VERSION 5.7 ;
BUSBITCHARS "[]" ;
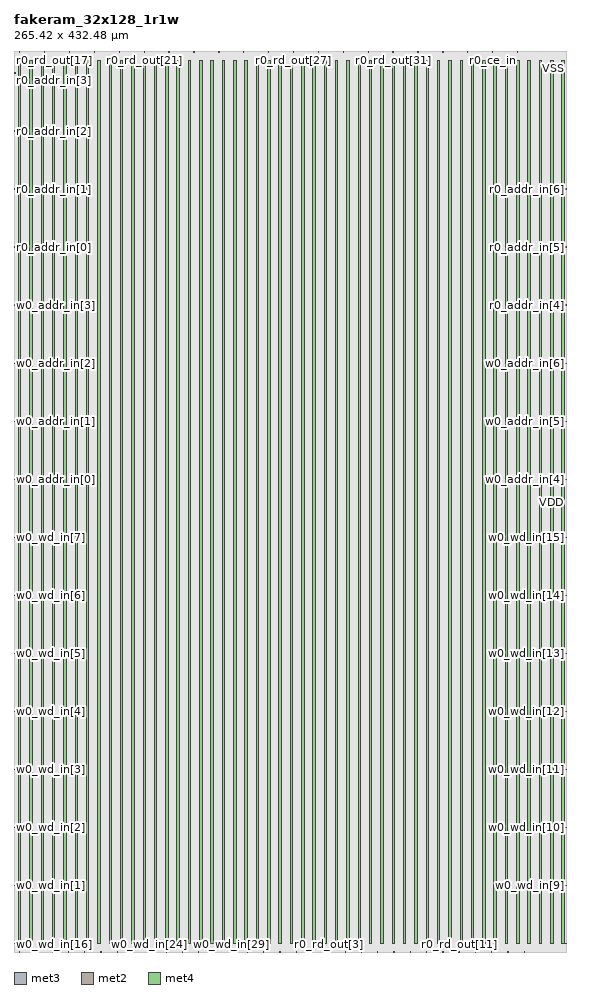
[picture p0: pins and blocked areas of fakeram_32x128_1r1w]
MACRO fakeram_32x128_1r1w
  FOREIGN fakeram_32x128_1r1w 0 0 ;
  SYMMETRY X Y R90 ;
  SIZE 265.420 BY 432.480 ;
  CLASS BLOCK ;
  PIN w0_wd_in[0]
    DIRECTION INPUT ;
    USE SIGNAL ;
    SHAPE ABUTMENT ;
    PORT
      LAYER met3 ;
      RECT 0.000 3.930 0.900 4.230 ;
    END
  END w0_wd_in[0]
  PIN w0_wd_in[1]
    DIRECTION INPUT ;
    USE SIGNAL ;
    SHAPE ABUTMENT ;
    PORT
      LAYER met3 ;
      RECT 0.000 31.810 0.900 32.110 ;
    END
  END w0_wd_in[1]
  PIN w0_wd_in[2]
    DIRECTION INPUT ;
    USE SIGNAL ;
    SHAPE ABUTMENT ;
    PORT
      LAYER met3 ;
      RECT 0.000 59.690 0.900 59.990 ;
    END
  END w0_wd_in[2]
  PIN w0_wd_in[3]
    DIRECTION INPUT ;
    USE SIGNAL ;
    SHAPE ABUTMENT ;
    PORT
      LAYER met3 ;
      RECT 0.000 87.570 0.900 87.870 ;
    END
  END w0_wd_in[3]
  PIN w0_wd_in[4]
    DIRECTION INPUT ;
    USE SIGNAL ;
    SHAPE ABUTMENT ;
    PORT
      LAYER met3 ;
      RECT 0.000 115.450 0.900 115.750 ;
    END
  END w0_wd_in[4]
  PIN w0_wd_in[5]
    DIRECTION INPUT ;
    USE SIGNAL ;
    SHAPE ABUTMENT ;
    PORT
      LAYER met3 ;
      RECT 0.000 143.330 0.900 143.630 ;
    END
  END w0_wd_in[5]
  PIN w0_wd_in[6]
    DIRECTION INPUT ;
    USE SIGNAL ;
    SHAPE ABUTMENT ;
    PORT
      LAYER met3 ;
      RECT 0.000 171.210 0.900 171.510 ;
    END
  END w0_wd_in[6]
  PIN w0_wd_in[7]
    DIRECTION INPUT ;
    USE SIGNAL ;
    SHAPE ABUTMENT ;
    PORT
      LAYER met3 ;
      RECT 0.000 199.090 0.900 199.390 ;
    END
  END w0_wd_in[7]
  PIN w0_wd_in[8]
    DIRECTION INPUT ;
    USE SIGNAL ;
    SHAPE ABUTMENT ;
    PORT
      LAYER met3 ;
      RECT 264.520 3.930 265.420 4.230 ;
    END
  END w0_wd_in[8]
  PIN w0_wd_in[9]
    DIRECTION INPUT ;
    USE SIGNAL ;
    SHAPE ABUTMENT ;
    PORT
      LAYER met3 ;
      RECT 264.520 31.810 265.420 32.110 ;
    END
  END w0_wd_in[9]
  PIN w0_wd_in[10]
    DIRECTION INPUT ;
    USE SIGNAL ;
    SHAPE ABUTMENT ;
    PORT
      LAYER met3 ;
      RECT 264.520 59.690 265.420 59.990 ;
    END
  END w0_wd_in[10]
  PIN w0_wd_in[11]
    DIRECTION INPUT ;
    USE SIGNAL ;
    SHAPE ABUTMENT ;
    PORT
      LAYER met3 ;
      RECT 264.520 87.570 265.420 87.870 ;
    END
  END w0_wd_in[11]
  PIN w0_wd_in[12]
    DIRECTION INPUT ;
    USE SIGNAL ;
    SHAPE ABUTMENT ;
    PORT
      LAYER met3 ;
      RECT 264.520 115.450 265.420 115.750 ;
    END
  END w0_wd_in[12]
  PIN w0_wd_in[13]
    DIRECTION INPUT ;
    USE SIGNAL ;
    SHAPE ABUTMENT ;
    PORT
      LAYER met3 ;
      RECT 264.520 143.330 265.420 143.630 ;
    END
  END w0_wd_in[13]
  PIN w0_wd_in[14]
    DIRECTION INPUT ;
    USE SIGNAL ;
    SHAPE ABUTMENT ;
    PORT
      LAYER met3 ;
      RECT 264.520 171.210 265.420 171.510 ;
    END
  END w0_wd_in[14]
  PIN w0_wd_in[15]
    DIRECTION INPUT ;
    USE SIGNAL ;
    SHAPE ABUTMENT ;
    PORT
      LAYER met3 ;
      RECT 264.520 199.090 265.420 199.390 ;
    END
  END w0_wd_in[15]
  PIN w0_wd_in[16]
    DIRECTION INPUT ;
    USE SIGNAL ;
    SHAPE ABUTMENT ;
    PORT
      LAYER met2 ;
      RECT 2.690 0.000 2.830 0.420 ;
    END
  END w0_wd_in[16]
  PIN w0_wd_in[17]
    DIRECTION INPUT ;
    USE SIGNAL ;
    SHAPE ABUTMENT ;
    PORT
      LAYER met2 ;
      RECT 10.510 0.000 10.650 0.420 ;
    END
  END w0_wd_in[17]
  PIN w0_wd_in[18]
    DIRECTION INPUT ;
    USE SIGNAL ;
    SHAPE ABUTMENT ;
    PORT
      LAYER met2 ;
      RECT 18.330 0.000 18.470 0.420 ;
    END
  END w0_wd_in[18]
  PIN w0_wd_in[19]
    DIRECTION INPUT ;
    USE SIGNAL ;
    SHAPE ABUTMENT ;
    PORT
      LAYER met2 ;
      RECT 26.150 0.000 26.290 0.420 ;
    END
  END w0_wd_in[19]
  PIN w0_wd_in[20]
    DIRECTION INPUT ;
    USE SIGNAL ;
    SHAPE ABUTMENT ;
    PORT
      LAYER met2 ;
      RECT 33.970 0.000 34.110 0.420 ;
    END
  END w0_wd_in[20]
  PIN w0_wd_in[21]
    DIRECTION INPUT ;
    USE SIGNAL ;
    SHAPE ABUTMENT ;
    PORT
      LAYER met2 ;
      RECT 41.790 0.000 41.930 0.420 ;
    END
  END w0_wd_in[21]
  PIN w0_wd_in[22]
    DIRECTION INPUT ;
    USE SIGNAL ;
    SHAPE ABUTMENT ;
    PORT
      LAYER met2 ;
      RECT 49.610 0.000 49.750 0.420 ;
    END
  END w0_wd_in[22]
  PIN w0_wd_in[23]
    DIRECTION INPUT ;
    USE SIGNAL ;
    SHAPE ABUTMENT ;
    PORT
      LAYER met2 ;
      RECT 57.430 0.000 57.570 0.420 ;
    END
  END w0_wd_in[23]
  PIN w0_wd_in[24]
    DIRECTION INPUT ;
    USE SIGNAL ;
    SHAPE ABUTMENT ;
    PORT
      LAYER met2 ;
      RECT 65.250 0.000 65.390 0.420 ;
    END
  END w0_wd_in[24]
  PIN w0_wd_in[25]
    DIRECTION INPUT ;
    USE SIGNAL ;
    SHAPE ABUTMENT ;
    PORT
      LAYER met2 ;
      RECT 73.070 0.000 73.210 0.420 ;
    END
  END w0_wd_in[25]
  PIN w0_wd_in[26]
    DIRECTION INPUT ;
    USE SIGNAL ;
    SHAPE ABUTMENT ;
    PORT
      LAYER met2 ;
      RECT 80.890 0.000 81.030 0.420 ;
    END
  END w0_wd_in[26]
  PIN w0_wd_in[27]
    DIRECTION INPUT ;
    USE SIGNAL ;
    SHAPE ABUTMENT ;
    PORT
      LAYER met2 ;
      RECT 88.710 0.000 88.850 0.420 ;
    END
  END w0_wd_in[27]
  PIN w0_wd_in[28]
    DIRECTION INPUT ;
    USE SIGNAL ;
    SHAPE ABUTMENT ;
    PORT
      LAYER met2 ;
      RECT 96.530 0.000 96.670 0.420 ;
    END
  END w0_wd_in[28]
  PIN w0_wd_in[29]
    DIRECTION INPUT ;
    USE SIGNAL ;
    SHAPE ABUTMENT ;
    PORT
      LAYER met2 ;
      RECT 104.350 0.000 104.490 0.420 ;
    END
  END w0_wd_in[29]
  PIN w0_wd_in[30]
    DIRECTION INPUT ;
    USE SIGNAL ;
    SHAPE ABUTMENT ;
    PORT
      LAYER met2 ;
      RECT 112.170 0.000 112.310 0.420 ;
    END
  END w0_wd_in[30]
  PIN w0_wd_in[31]
    DIRECTION INPUT ;
    USE SIGNAL ;
    SHAPE ABUTMENT ;
    PORT
      LAYER met2 ;
      RECT 119.990 0.000 120.130 0.420 ;
    END
  END w0_wd_in[31]
  PIN r0_rd_out[0]
    DIRECTION OUTPUT ;
    USE SIGNAL ;
    SHAPE ABUTMENT ;
    PORT
      LAYER met2 ;
      RECT 127.810 0.000 127.950 0.420 ;
    END
  END r0_rd_out[0]
  PIN r0_rd_out[1]
    DIRECTION OUTPUT ;
    USE SIGNAL ;
    SHAPE ABUTMENT ;
    PORT
      LAYER met2 ;
      RECT 135.630 0.000 135.770 0.420 ;
    END
  END r0_rd_out[1]
  PIN r0_rd_out[2]
    DIRECTION OUTPUT ;
    USE SIGNAL ;
    SHAPE ABUTMENT ;
    PORT
      LAYER met2 ;
      RECT 143.450 0.000 143.590 0.420 ;
    END
  END r0_rd_out[2]
  PIN r0_rd_out[3]
    DIRECTION OUTPUT ;
    USE SIGNAL ;
    SHAPE ABUTMENT ;
    PORT
      LAYER met2 ;
      RECT 151.270 0.000 151.410 0.420 ;
    END
  END r0_rd_out[3]
  PIN r0_rd_out[4]
    DIRECTION OUTPUT ;
    USE SIGNAL ;
    SHAPE ABUTMENT ;
    PORT
      LAYER met2 ;
      RECT 159.090 0.000 159.230 0.420 ;
    END
  END r0_rd_out[4]
  PIN r0_rd_out[5]
    DIRECTION OUTPUT ;
    USE SIGNAL ;
    SHAPE ABUTMENT ;
    PORT
      LAYER met2 ;
      RECT 166.910 0.000 167.050 0.420 ;
    END
  END r0_rd_out[5]
  PIN r0_rd_out[6]
    DIRECTION OUTPUT ;
    USE SIGNAL ;
    SHAPE ABUTMENT ;
    PORT
      LAYER met2 ;
      RECT 174.730 0.000 174.870 0.420 ;
    END
  END r0_rd_out[6]
  PIN r0_rd_out[7]
    DIRECTION OUTPUT ;
    USE SIGNAL ;
    SHAPE ABUTMENT ;
    PORT
      LAYER met2 ;
      RECT 182.550 0.000 182.690 0.420 ;
    END
  END r0_rd_out[7]
  PIN r0_rd_out[8]
    DIRECTION OUTPUT ;
    USE SIGNAL ;
    SHAPE ABUTMENT ;
    PORT
      LAYER met2 ;
      RECT 190.370 0.000 190.510 0.420 ;
    END
  END r0_rd_out[8]
  PIN r0_rd_out[9]
    DIRECTION OUTPUT ;
    USE SIGNAL ;
    SHAPE ABUTMENT ;
    PORT
      LAYER met2 ;
      RECT 198.190 0.000 198.330 0.420 ;
    END
  END r0_rd_out[9]
  PIN r0_rd_out[10]
    DIRECTION OUTPUT ;
    USE SIGNAL ;
    SHAPE ABUTMENT ;
    PORT
      LAYER met2 ;
      RECT 206.010 0.000 206.150 0.420 ;
    END
  END r0_rd_out[10]
  PIN r0_rd_out[11]
    DIRECTION OUTPUT ;
    USE SIGNAL ;
    SHAPE ABUTMENT ;
    PORT
      LAYER met2 ;
      RECT 213.830 0.000 213.970 0.420 ;
    END
  END r0_rd_out[11]
  PIN r0_rd_out[12]
    DIRECTION OUTPUT ;
    USE SIGNAL ;
    SHAPE ABUTMENT ;
    PORT
      LAYER met2 ;
      RECT 221.650 0.000 221.790 0.420 ;
    END
  END r0_rd_out[12]
  PIN r0_rd_out[13]
    DIRECTION OUTPUT ;
    USE SIGNAL ;
    SHAPE ABUTMENT ;
    PORT
      LAYER met2 ;
      RECT 229.470 0.000 229.610 0.420 ;
    END
  END r0_rd_out[13]
  PIN r0_rd_out[14]
    DIRECTION OUTPUT ;
    USE SIGNAL ;
    SHAPE ABUTMENT ;
    PORT
      LAYER met2 ;
      RECT 237.290 0.000 237.430 0.420 ;
    END
  END r0_rd_out[14]
  PIN r0_rd_out[15]
    DIRECTION OUTPUT ;
    USE SIGNAL ;
    SHAPE ABUTMENT ;
    PORT
      LAYER met2 ;
      RECT 245.110 0.000 245.250 0.420 ;
    END
  END r0_rd_out[15]
  PIN r0_rd_out[16]
    DIRECTION OUTPUT ;
    USE SIGNAL ;
    SHAPE ABUTMENT ;
    PORT
      LAYER met2 ;
      RECT 2.690 432.060 2.830 432.480 ;
    END
  END r0_rd_out[16]
  PIN r0_rd_out[17]
    DIRECTION OUTPUT ;
    USE SIGNAL ;
    SHAPE ABUTMENT ;
    PORT
      LAYER met2 ;
      RECT 14.650 432.060 14.790 432.480 ;
    END
  END r0_rd_out[17]
  PIN r0_rd_out[18]
    DIRECTION OUTPUT ;
    USE SIGNAL ;
    SHAPE ABUTMENT ;
    PORT
      LAYER met2 ;
      RECT 26.610 432.060 26.750 432.480 ;
    END
  END r0_rd_out[18]
  PIN r0_rd_out[19]
    DIRECTION OUTPUT ;
    USE SIGNAL ;
    SHAPE ABUTMENT ;
    PORT
      LAYER met2 ;
      RECT 38.570 432.060 38.710 432.480 ;
    END
  END r0_rd_out[19]
  PIN r0_rd_out[20]
    DIRECTION OUTPUT ;
    USE SIGNAL ;
    SHAPE ABUTMENT ;
    PORT
      LAYER met2 ;
      RECT 50.530 432.060 50.670 432.480 ;
    END
  END r0_rd_out[20]
  PIN r0_rd_out[21]
    DIRECTION OUTPUT ;
    USE SIGNAL ;
    SHAPE ABUTMENT ;
    PORT
      LAYER met2 ;
      RECT 62.490 432.060 62.630 432.480 ;
    END
  END r0_rd_out[21]
  PIN r0_rd_out[22]
    DIRECTION OUTPUT ;
    USE SIGNAL ;
    SHAPE ABUTMENT ;
    PORT
      LAYER met2 ;
      RECT 74.450 432.060 74.590 432.480 ;
    END
  END r0_rd_out[22]
  PIN r0_rd_out[23]
    DIRECTION OUTPUT ;
    USE SIGNAL ;
    SHAPE ABUTMENT ;
    PORT
      LAYER met2 ;
      RECT 86.410 432.060 86.550 432.480 ;
    END
  END r0_rd_out[23]
  PIN r0_rd_out[24]
    DIRECTION OUTPUT ;
    USE SIGNAL ;
    SHAPE ABUTMENT ;
    PORT
      LAYER met2 ;
      RECT 98.370 432.060 98.510 432.480 ;
    END
  END r0_rd_out[24]
  PIN r0_rd_out[25]
    DIRECTION OUTPUT ;
    USE SIGNAL ;
    SHAPE ABUTMENT ;
    PORT
      LAYER met2 ;
      RECT 110.330 432.060 110.470 432.480 ;
    END
  END r0_rd_out[25]
  PIN r0_rd_out[26]
    DIRECTION OUTPUT ;
    USE SIGNAL ;
    SHAPE ABUTMENT ;
    PORT
      LAYER met2 ;
      RECT 122.290 432.060 122.430 432.480 ;
    END
  END r0_rd_out[26]
  PIN r0_rd_out[27]
    DIRECTION OUTPUT ;
    USE SIGNAL ;
    SHAPE ABUTMENT ;
    PORT
      LAYER met2 ;
      RECT 134.250 432.060 134.390 432.480 ;
    END
  END r0_rd_out[27]
  PIN r0_rd_out[28]
    DIRECTION OUTPUT ;
    USE SIGNAL ;
    SHAPE ABUTMENT ;
    PORT
      LAYER met2 ;
      RECT 146.210 432.060 146.350 432.480 ;
    END
  END r0_rd_out[28]
  PIN r0_rd_out[29]
    DIRECTION OUTPUT ;
    USE SIGNAL ;
    SHAPE ABUTMENT ;
    PORT
      LAYER met2 ;
      RECT 158.170 432.060 158.310 432.480 ;
    END
  END r0_rd_out[29]
  PIN r0_rd_out[30]
    DIRECTION OUTPUT ;
    USE SIGNAL ;
    SHAPE ABUTMENT ;
    PORT
      LAYER met2 ;
      RECT 170.130 432.060 170.270 432.480 ;
    END
  END r0_rd_out[30]
  PIN r0_rd_out[31]
    DIRECTION OUTPUT ;
    USE SIGNAL ;
    SHAPE ABUTMENT ;
    PORT
      LAYER met2 ;
      RECT 182.090 432.060 182.230 432.480 ;
    END
  END r0_rd_out[31]
  PIN w0_addr_in[0]
    DIRECTION INPUT ;
    USE SIGNAL ;
    SHAPE ABUTMENT ;
    PORT
      LAYER met3 ;
      RECT 0.000 226.970 0.900 227.270 ;
    END
  END w0_addr_in[0]
  PIN w0_addr_in[1]
    DIRECTION INPUT ;
    USE SIGNAL ;
    SHAPE ABUTMENT ;
    PORT
      LAYER met3 ;
      RECT 0.000 254.850 0.900 255.150 ;
    END
  END w0_addr_in[1]
  PIN w0_addr_in[2]
    DIRECTION INPUT ;
    USE SIGNAL ;
    SHAPE ABUTMENT ;
    PORT
      LAYER met3 ;
      RECT 0.000 282.730 0.900 283.030 ;
    END
  END w0_addr_in[2]
  PIN w0_addr_in[3]
    DIRECTION INPUT ;
    USE SIGNAL ;
    SHAPE ABUTMENT ;
    PORT
      LAYER met3 ;
      RECT 0.000 310.610 0.900 310.910 ;
    END
  END w0_addr_in[3]
  PIN w0_addr_in[4]
    DIRECTION INPUT ;
    USE SIGNAL ;
    SHAPE ABUTMENT ;
    PORT
      LAYER met3 ;
      RECT 264.520 226.970 265.420 227.270 ;
    END
  END w0_addr_in[4]
  PIN w0_addr_in[5]
    DIRECTION INPUT ;
    USE SIGNAL ;
    SHAPE ABUTMENT ;
    PORT
      LAYER met3 ;
      RECT 264.520 254.850 265.420 255.150 ;
    END
  END w0_addr_in[5]
  PIN w0_addr_in[6]
    DIRECTION INPUT ;
    USE SIGNAL ;
    SHAPE ABUTMENT ;
    PORT
      LAYER met3 ;
      RECT 264.520 282.730 265.420 283.030 ;
    END
  END w0_addr_in[6]
  PIN r0_addr_in[0]
    DIRECTION INPUT ;
    USE SIGNAL ;
    SHAPE ABUTMENT ;
    PORT
      LAYER met3 ;
      RECT 0.000 338.490 0.900 338.790 ;
    END
  END r0_addr_in[0]
  PIN r0_addr_in[1]
    DIRECTION INPUT ;
    USE SIGNAL ;
    SHAPE ABUTMENT ;
    PORT
      LAYER met3 ;
      RECT 0.000 366.370 0.900 366.670 ;
    END
  END r0_addr_in[1]
  PIN r0_addr_in[2]
    DIRECTION INPUT ;
    USE SIGNAL ;
    SHAPE ABUTMENT ;
    PORT
      LAYER met3 ;
      RECT 0.000 394.250 0.900 394.550 ;
    END
  END r0_addr_in[2]
  PIN r0_addr_in[3]
    DIRECTION INPUT ;
    USE SIGNAL ;
    SHAPE ABUTMENT ;
    PORT
      LAYER met3 ;
      RECT 0.000 422.130 0.900 422.430 ;
    END
  END r0_addr_in[3]
  PIN r0_addr_in[4]
    DIRECTION INPUT ;
    USE SIGNAL ;
    SHAPE ABUTMENT ;
    PORT
      LAYER met3 ;
      RECT 264.520 310.610 265.420 310.910 ;
    END
  END r0_addr_in[4]
  PIN r0_addr_in[5]
    DIRECTION INPUT ;
    USE SIGNAL ;
    SHAPE ABUTMENT ;
    PORT
      LAYER met3 ;
      RECT 264.520 338.490 265.420 338.790 ;
    END
  END r0_addr_in[5]
  PIN r0_addr_in[6]
    DIRECTION INPUT ;
    USE SIGNAL ;
    SHAPE ABUTMENT ;
    PORT
      LAYER met3 ;
      RECT 264.520 366.370 265.420 366.670 ;
    END
  END r0_addr_in[6]
  PIN w0_we_in
    DIRECTION INPUT ;
    USE SIGNAL ;
    SHAPE ABUTMENT ;
    PORT
      LAYER met2 ;
      RECT 194.050 432.060 194.190 432.480 ;
    END
  END w0_we_in
  PIN w0_ce_in
    DIRECTION INPUT ;
    USE SIGNAL ;
    SHAPE ABUTMENT ;
    PORT
      LAYER met2 ;
      RECT 206.010 432.060 206.150 432.480 ;
    END
  END w0_ce_in
  PIN w0_clk
    DIRECTION INPUT ;
    USE SIGNAL ;
    SHAPE ABUTMENT ;
    PORT
      LAYER met2 ;
      RECT 217.970 432.060 218.110 432.480 ;
    END
  END w0_clk
  PIN r0_ce_in
    DIRECTION INPUT ;
    USE SIGNAL ;
    SHAPE ABUTMENT ;
    PORT
      LAYER met2 ;
      RECT 229.930 432.060 230.070 432.480 ;
    END
  END r0_ce_in
  PIN r0_clk
    DIRECTION INPUT ;
    USE SIGNAL ;
    SHAPE ABUTMENT ;
    PORT
      LAYER met2 ;
      RECT 241.890 432.060 242.030 432.480 ;
    END
  END r0_clk
  PIN VSS
    DIRECTION INOUT ;
    USE GROUND ;
    PORT
      LAYER met4 ;
      RECT 2.160 4.080 3.360 428.400 ;
      RECT 13.040 4.080 14.240 428.400 ;
      RECT 23.920 4.080 25.120 428.400 ;
      RECT 34.800 4.080 36.000 428.400 ;
      RECT 45.680 4.080 46.880 428.400 ;
      RECT 56.560 4.080 57.760 428.400 ;
      RECT 67.440 4.080 68.640 428.400 ;
      RECT 78.320 4.080 79.520 428.400 ;
      RECT 89.200 4.080 90.400 428.400 ;
      RECT 100.080 4.080 101.280 428.400 ;
      RECT 110.960 4.080 112.160 428.400 ;
      RECT 121.840 4.080 123.040 428.400 ;
      RECT 132.720 4.080 133.920 428.400 ;
      RECT 143.600 4.080 144.800 428.400 ;
      RECT 154.480 4.080 155.680 428.400 ;
      RECT 165.360 4.080 166.560 428.400 ;
      RECT 176.240 4.080 177.440 428.400 ;
      RECT 187.120 4.080 188.320 428.400 ;
      RECT 198.000 4.080 199.200 428.400 ;
      RECT 208.880 4.080 210.080 428.400 ;
      RECT 219.760 4.080 220.960 428.400 ;
      RECT 230.640 4.080 231.840 428.400 ;
      RECT 241.520 4.080 242.720 428.400 ;
      RECT 252.400 4.080 253.600 428.400 ;
      RECT 263.280 4.080 264.480 428.400 ;
    END
  END VSS
  PIN VDD
    DIRECTION INOUT ;
    USE POWER ;
    PORT
      LAYER met4 ;
      RECT 7.600 4.080 8.800 428.400 ;
      RECT 18.480 4.080 19.680 428.400 ;
      RECT 29.360 4.080 30.560 428.400 ;
      RECT 40.240 4.080 41.440 428.400 ;
      RECT 51.120 4.080 52.320 428.400 ;
      RECT 62.000 4.080 63.200 428.400 ;
      RECT 72.880 4.080 74.080 428.400 ;
      RECT 83.760 4.080 84.960 428.400 ;
      RECT 94.640 4.080 95.840 428.400 ;
      RECT 105.520 4.080 106.720 428.400 ;
      RECT 116.400 4.080 117.600 428.400 ;
      RECT 127.280 4.080 128.480 428.400 ;
      RECT 138.160 4.080 139.360 428.400 ;
      RECT 149.040 4.080 150.240 428.400 ;
      RECT 159.920 4.080 161.120 428.400 ;
      RECT 170.800 4.080 172.000 428.400 ;
      RECT 181.680 4.080 182.880 428.400 ;
      RECT 192.560 4.080 193.760 428.400 ;
      RECT 203.440 4.080 204.640 428.400 ;
      RECT 214.320 4.080 215.520 428.400 ;
      RECT 225.200 4.080 226.400 428.400 ;
      RECT 236.080 4.080 237.280 428.400 ;
      RECT 246.960 4.080 248.160 428.400 ;
      RECT 257.840 4.080 259.040 428.400 ;
    END
  END VDD
  OBS
    LAYER met1 ;
    RECT 0 0 265.420 432.480 ;
    LAYER met2 ;
    RECT 0 0 265.420 432.480 ;
    LAYER met3 ;
    RECT 0 0 265.420 432.480 ;
    LAYER met4 ;
    RECT 0 0 265.420 432.480 ;
  END
END fakeram_32x128_1r1w

END LIBRARY
